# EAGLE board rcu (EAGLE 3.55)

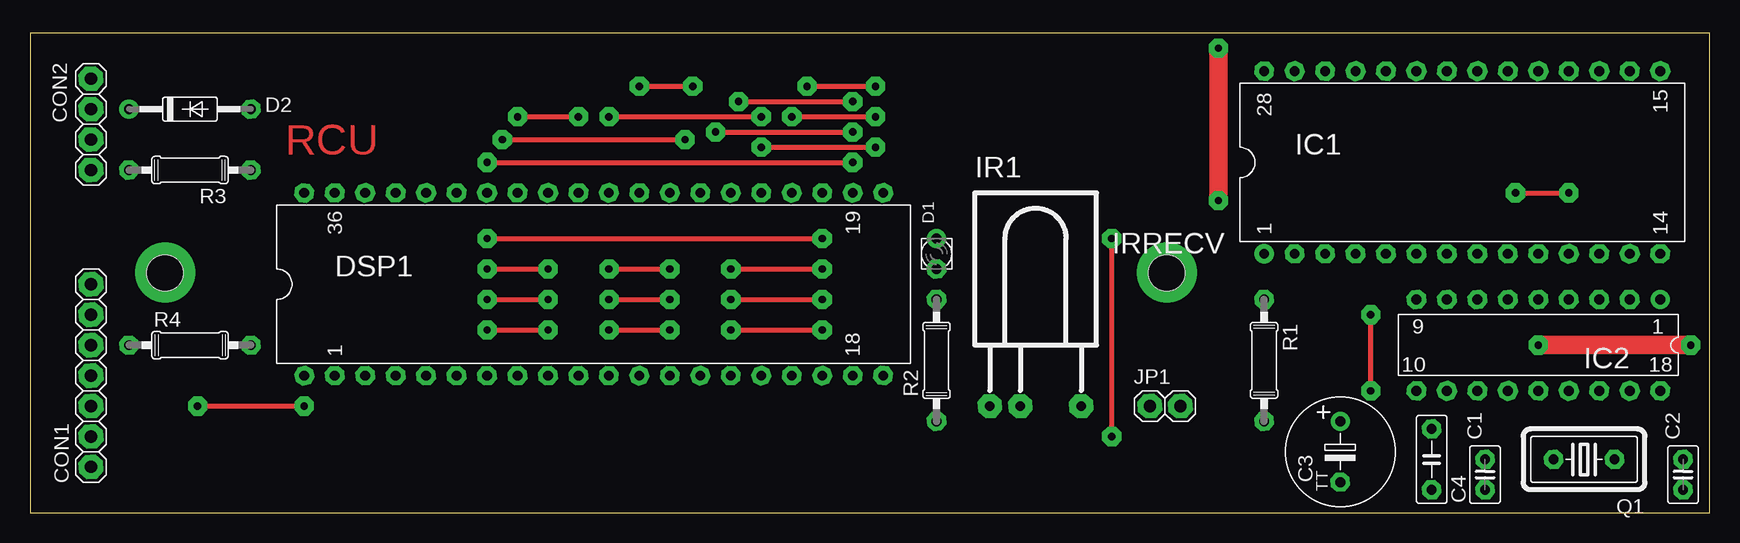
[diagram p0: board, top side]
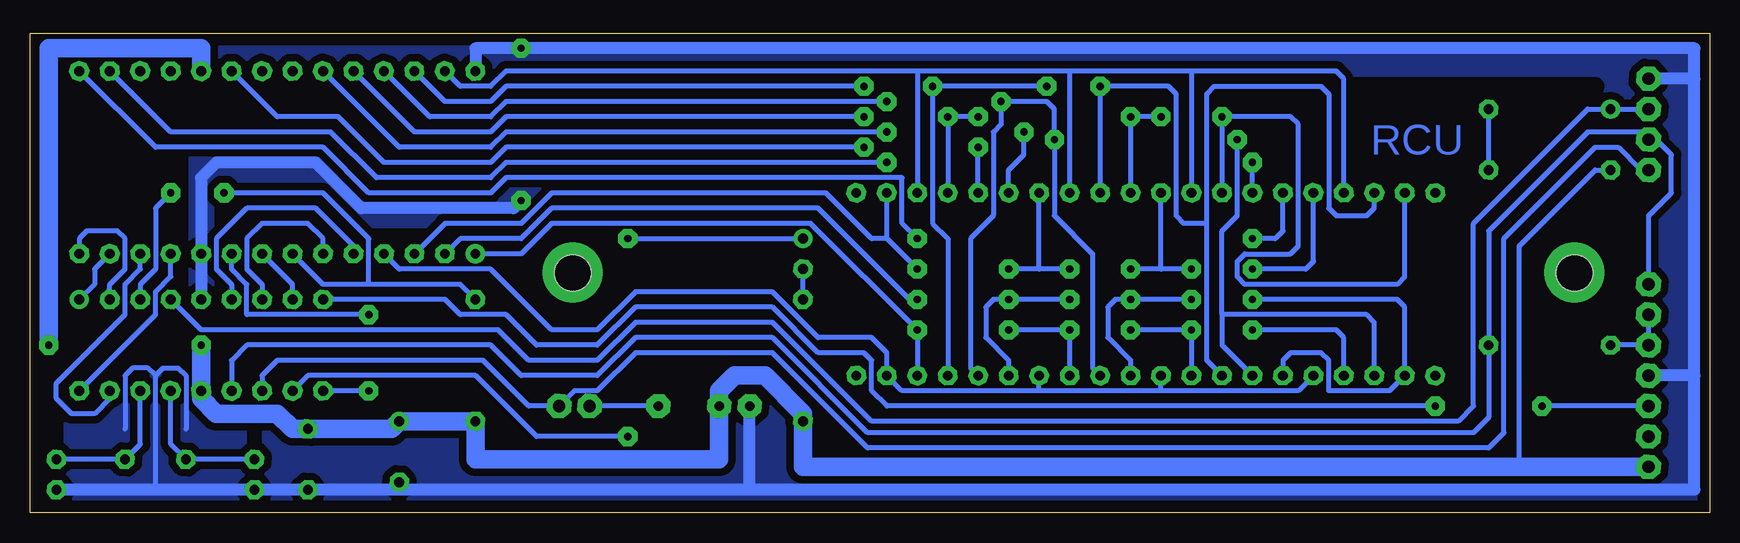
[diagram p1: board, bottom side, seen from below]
Size 140 x 40 mm. Coordinates in mm from the lower left corner, seen from the top.
Outline: 0,0 140,0 140,40 0,40 0,0
Copper layers used: Top, Bottom
bRestrict: 12 lines

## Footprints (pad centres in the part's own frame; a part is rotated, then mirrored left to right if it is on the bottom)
,5-2 = drill 0.813 pad 1.6 octagon:  -1.27,0;  1.27,0
5D9 = drill 0.813 pad 1.6 octagon:  -2.54,0 | drill 0.813 pad 1.6 round:  2.54,0
B2,5 = drill 0.813 pad 1.6 octagon:  -2.54,0;  2.54,0
07 = drill 1.016 pad 2.032 octagon:  -7.62,0;  -5.08,0;  -2.54,0;  0,0;  2.54,0;  5.08,0;  7.62,0
04 = drill 1.016 pad 2.032 octagon:  -3.81,0;  -1.27,0;  1.27,0;  3.81,0
D2 = drill 0.813 pad 1.6 octagon:  -1.27,0 | drill 0.813 pad 1.6 round:  1.27,0
35-10 = drill 0.813 pad 1.6 round:  -5.08,0 | drill 0.813 pad 1.6 octagon:  5.08,0
L36+4 = drill 0.813 pad 1.6 octagon:  -21.59,-7.62;  -19.05,-7.62;  -16.51,-7.62;  -13.97,-7.62;  -11.43,-7.62;  -8.89,-7.62;  -6.35,-7.62;  -3.81,-7.62;  -1.27,-7.62;  1.27,-7.62;  3.81,-7.62;  6.35,-7.62;  8.89,-7.62;  11.43,-7.62;  13.97,-7.62;  16.51,-7.62;  19.05,-7.62;  21.59,-7.62;  21.59,7.62;  19.05,7.62;  16.51,7.62;  13.97,7.62;  11.43,7.62;  8.89,7.62;  6.35,7.62;  3.81,7.62;  1.27,7.62;  -1.27,7.62;  -3.81,7.62;  -6.35,7.62;  -8.89,7.62;  -11.43,7.62;  -13.97,7.62;  -16.51,7.62;  -19.05,7.62;  -21.59,7.62;  -24.13,7.62;  -24.13,-7.62;  24.13,-7.62;  24.13,7.62
L28-6 = drill 0.813 pad 1.6 round:  -16.51,-7.62 | drill 0.813 pad 1.6 octagon:  -13.97,-7.62;  -11.43,-7.62;  -8.89,-7.62;  -6.35,-7.62;  -3.81,-7.62;  -1.27,-7.62;  1.27,-7.62;  3.81,-7.62;  6.35,-7.62;  8.89,-7.62;  11.43,-7.62;  13.97,-7.62;  16.51,-7.62;  16.51,7.62;  13.97,7.62;  11.43,7.62;  8.89,7.62;  6.35,7.62;  3.81,7.62;  1.27,7.62;  -1.27,7.62;  -3.81,7.62;  -6.35,7.62;  -8.89,7.62;  -11.43,7.62;  -13.97,7.62;  -16.51,7.62
L18 = drill 0.813 pad 1.6 round:  -10.16,-3.81 | drill 0.813 pad 1.6 octagon:  -7.62,-3.81;  -5.08,-3.81;  -2.54,-3.81;  0,-3.81;  2.54,-3.81;  5.08,-3.81;  7.62,-3.81;  10.16,-3.81;  10.16,3.81;  7.62,3.81;  5.08,3.81;  2.54,3.81;  0,3.81;  -2.54,3.81;  -5.08,3.81;  -7.62,3.81;  -10.16,3.81
RECV = drill 0.813 pad 2 octagon:  -3.81,-12.7;  -1.27,-12.7;  3.81,-12.7
02 = drill 1.016 pad 2.032 octagon:  -1.27,0;  1.27,0
18U-V = drill 0.813 pad 1.6 octagon:  -2.54,0;  2.54,0
07/10 = drill 0.813 pad 1.6 octagon:  -5.08,0;  5.08,0
AME = hole 3: -41.75,0; 41.75,0

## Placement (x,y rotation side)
C1  27p  [,5-2]  121.28,3.17 90 top
C2  27p  [,5-2]  137.79,3.17 90 top
C3  10u/10V  [5D9]  109.22,5.08 90 top
C4  100n  [B2,5]  116.84,4.45 270 top
CON1  1x7  [07]  5.08,11.43 90 top
CON2  1x4  [04]  5.08,32.38 270 top
D1  LED2  [D2]  75.56,21.59 90 top
D2  1N4148  [35-10]  13.34,33.66 0 top
DSP1  LEDDISP  [L36+4]  46.99,19.05 0 top
IC1  ICM7218C  [L28-6]  119.38,29.21 0 top
IC2  16C84P  [L18]  125.73,13.97 180 top
IR1  IRRECV  [RECV]  83.82,21.59 0 top
JP1  1x2  [02]  94.61,8.89 0 top
Q1  10MHz  [18U-V]  129.54,4.45 180 top
R1  4k7  [07/10]  102.87,12.7 270 top
R2  470R  [07/10]  75.56,12.7 90 top
R3  2k2  [07/10]  13.34,28.57 180 top
R4  22k  [07/10]  13.34,13.97 0 top
U$2  [AME]  53,20 0 top

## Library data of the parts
C1 C2 C4 = cap-wi
C3 = cap-tant
CON1 CON2 JP1 = pinhead
D1 = led
D2 = diode
DSP1 IR1 U$2 = display
IC1 = maxim
IC2 = pic
Q1 = quartz
R1-R4 = r

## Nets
+5V: C3. C4. CON1. IC1. IC2. IR1. R1. R2. R3.
DIGIT1: DSP1. IC1.
DIGIT2: DSP1. IC1.
DIGIT3: DSP1. IC1.
DIGIT4: DSP1. IC1.
DP: DSP1. IC1.
GND: C1. C2. C3. C4. CON1. CON2. IC1. IC2. IR1.
N$1: IC1. IC2.
N$2: IC1. IC2.
N$3: C1. IC2. Q1.
N$4: IC1. IC2.
N$5: IC1. IC2.
N$6: IC1. IC2.
N$7: IC1. IC2.
N$8: IC1. IC2. R1.
N$9: IC1. IC2.
N$10: IC1. IC2.
N$11: C2. IC2. Q1.
N$12: D1. R2.
N$13: D1. IC2.
N$14: CON2. D2. IC2.
N$15: CON1. CON2. IC2. R4.
N$16: CON2. IC2. JP1.
N$17: D2. R3.
N$18: CON1. R4.
N$19: IR1. JP1.
N$20: CON1. IC2.
SEG0: DSP1. IC1.
SEG1: DSP1. IC1.
SEG2: DSP1. IC1.
SEG3: DSP1. IC1.
SEG4: DSP1. IC1.
SEG5: DSP1. IC1.
SEG6: DSP1. IC1.

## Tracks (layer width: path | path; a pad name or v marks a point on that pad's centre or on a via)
+5V  (via drill 0.61 pad 1.6)
  Top 1.524: v125.73,13.97 v138.43,13.97
  Bottom 0.406: 15.88,3.81 15.88,22.23 9.53,28.57 R3.
  Bottom 1.016: 75.56,7.62 75.56,8.26
  Bottom 1.524: v125.73,13.97 125.73,10.16 125.73,9.53 124.46,8.26 119.38,8.26 118.11,6.99 116.84,6.99 109.86,6.99 C3. R1. 102.87,4.45 82.55,4.45 82.55,8.89 82.55,10.16 81.28,11.43 78.74,11.43 75.56,8.26 | v138.43,13.97 138.43,38.73 125.73,38.73 125.73,36.83 | 75.56,7.62 75.56,3.81 15.88,3.81 5.08,3.81
DIGIT1  (via drill 0.61 pad 1.6)
  Top 0.406: v38.1,22.86 v66.04,22.86
  Bottom 0.406: 135.89,36.83 129.54,30.48 115.57,30.48 111.76,26.67 101.6,26.67 100.33,27.94 67.31,27.94 67.31,24.13 v66.04,22.86 | v38.1,22.86 36.2,22.86 35.56,23.5 35.56,26.67
DIGIT2  (via drill 0.61 pad 1.6)
  Top 0.406: v38.1,29.21 v68.58,29.21
  Bottom 0.406: 133.35,36.83 128.27,31.75 114.94,31.75 111.12,27.94 101.6,27.94 100.33,29.21 v68.58,29.21 | 38.1,26.67 v38.1,29.21
DIGIT3  (via drill 0.61 pad 1.6)
  Top 0.406: v57.15,31.75 v68.58,31.75
  Bottom 0.406: 115.57,36.83 109.22,30.48 101.6,30.48 100.33,31.75 v68.58,31.75 | 58.42,26.67 58.42,28.57 57.15,29.84 v57.15,31.75
DIGIT4  (via drill 0.61 pad 1.6)
  Top 0.406: v60.96,30.48 v70.48,30.48
  Bottom 0.406: 123.19,36.83 119.38,33.02 114.3,33.02 110.49,29.21 101.6,29.21 100.33,30.48 v70.48,30.48 | 60.96,26.67 v60.96,30.48
DP
  Bottom 0.406: 110.49,21.59 109.22,20.32 101.6,20.32 96.52,15.24 92.71,15.24 89.53,18.41 78.11,18.41 74.3,14.61 69.85,14.61 68.58,13.34 68.58,11.43 67.31,10.16 55.88,10.16 | 33.02,11.43 34.29,10.16 45.72,10.16 | 45.72,10.16 45.72,11.43 | 45.72,10.16 55.88,10.16 | 55.88,10.16 55.88,11.43
GND  (via drill 0.61 pad 1.6)
  Top 1.524: v99.06,38.73 v99.06,26.04
  Bottom 0.406: 129.54,1.91 129.54,11.43 | 129.54,11.43 130.18,12.06 131.44,12.06 132.08,11.43 132.08,6.99 | 129.54,11.43 128.91,12.06 127.64,12.06 127,11.43 127,6.99
  Bottom 1.016: 137.79,1.91 129.54,1.91 121.28,1.91 C4. 109.22,1.91 | 109.22,1.91 109.22,2.54 | 125.73,17.78 125.73,21.59 125.73,27.94 124.46,29.21 116.2,29.21 112.39,25.4 99.69,25.4 v99.06,26.04 | 80.01,1.91 80.01,8.89 | 1.27,11.43 1.27,36.2 | 80.01,1.91 1.27,1.91 1.27,11.43 | 80.01,1.91 109.22,1.91 | IC1. 102.87,38.73 v99.06,38.73 1.27,38.73 1.27,36.2 | 1.27,11.43 5.08,11.43 | 1.27,36.2 5.08,36.2
  pour Bottom (isolate 0.635, no thermals): 0.13,39.88 0.13,0.13 139.83,0.13 139.83,39.88
N$1
  Bottom 0.406: 123.19,17.78 123.19,19.05 124.46,20.32 124.46,22.86 121.92,25.4 116.2,25.4 113.03,22.23 113.03,21.59
N$2
  Bottom 0.406: 120.65,17.78 120.65,19.05 121.92,20.32 121.92,22.86 120.65,24.13 116.84,24.13 115.57,22.86 115.57,21.59
N$3
  Bottom 0.406: 128.27,10.16 128.27,5.71 Q1. C1.
N$4
  Bottom 0.406: 130.81,21.59 130.81,20.32 132.08,19.05 132.08,16.51 137.79,10.79 137.79,9.53 136.53,8.26 134.62,8.26 133.35,9.53 133.35,10.16
N$5
  Bottom 0.406: 128.27,21.59 128.27,19.68 129.54,18.41 129.54,16.51 IC2.
N$6
  Bottom 0.406: 133.35,21.59 134.62,20.32 134.62,19.05 135.89,17.78
N$7
  Bottom 0.406: 135.89,21.59 135.89,22.86 135.25,23.5 132.72,23.5 132.08,22.86 132.08,20.32 133.35,19.05 133.35,17.78
N$8  (via drill 0.61 pad 1.6)
  Top 0.406: v123.83,26.67 v128.27,26.67
  Bottom 0.406: 118.11,21.59 115.57,19.05 111.76,19.05 | 111.76,19.05 104.14,19.05 102.87,17.78 | 130.81,17.78 130.81,19.05 129.54,20.32 129.54,25.4 v128.27,26.67 | 111.76,19.05 111.76,22.86 115.57,26.67 v123.83,26.67
N$9  (via drill 0.61 pad 1.6)
  Top 0.406: v111.76,10.16 v111.76,16.51
  Bottom 0.406: v111.76,10.16 115.57,10.16 | 123.19,21.59 123.19,20.32 121.92,19.05 121.92,16.51 v111.76,16.51
N$10
  Bottom 0.406: 120.65,21.59 118.11,19.05 118.11,17.78
N$11
  Bottom 0.406: 130.81,10.16 130.81,5.71 132.08,4.45 C2.
N$12
  Bottom 0.406: R2. 75.56,20.32
N$13  (via drill 0.61 pad 1.6)
  Top 0.406: v90.17,6.35 v90.17,22.86
  Bottom 0.406: 118.11,10.16 116.84,11.43 102.87,11.43 97.79,6.35 v90.17,6.35 | v90.17,22.86 D1.
N$14
  Bottom 0.406: 128.27,17.78 125.73,15.24 100.97,15.24 98.42,12.7 92.71,12.7 89.53,15.88 78.11,15.88 69.85,7.62 20.95,7.62 19.68,8.89 19.68,24.13 10.16,33.66 8.26,33.66 5.08,33.66
N$15
  Bottom 0.406: 123.19,10.16 123.19,12.7 121.92,13.97 101.6,13.97 99.06,11.43 92.71,11.43 89.53,14.61 78.11,14.61 70.17,6.67 19.68,6.67 18.41,7.94 R4. 18.41,23.5 10.16,31.75 5.71,31.75 5.08,31.11 4.45,31.11 3.17,29.84 3.17,26.67 5.08,24.77 CON1.
N$16
  Bottom 0.406: 120.65,10.16 120.65,11.43 119.38,12.7 102.23,12.7 98.42,8.89 JP1. 94.61,10.16 92.71,10.16 89.53,13.34 78.11,13.34 70.17,5.4 18.41,5.4 17.14,6.67 17.14,22.86 9.53,30.48 7.62,30.48 5.71,28.57 CON2.
N$17
  Bottom 0.406: 18.41,28.57 D2.
N$18
  Bottom 0.406: 5.08,16.51 5.08,13.97 8.26,13.97
N$19
  Bottom 0.406: IR1. 93.34,8.89
N$20  (via drill 0.61 pad 1.6)
  Top 0.406: v13.97,8.89 v22.86,8.89
  Bottom 0.406: 115.57,17.78 105.41,17.78 104.14,16.51 100.33,16.51 97.79,13.97 92.71,13.97 89.53,17.14 78.11,17.14 74.3,13.34 70.48,13.34 69.85,12.7 69.85,10.16 68.58,8.89 v22.86,8.89 | 5.08,8.89 v13.97,8.89
N$21  (via drill 0.61 pad 5)
  other vias: 11.25,20.01
N$22  (via drill 0.61 pad 5)
  other vias: 94.76,20.01
SEG0
  Bottom 0.406: 105.41,36.83 104.14,35.56 101.6,35.56 100.33,36.83 66.04,36.83 | 30.48,26.67 30.48,36.2 31.11,36.83 43.18,36.83 | 43.18,36.83 43.18,26.67 | 53.34,36.83 53.34,26.67 | 66.04,36.83 66.04,26.67 | 53.34,36.83 66.04,36.83 | 43.18,36.83 53.34,36.83
SEG1  (via drill 0.61 pad 1.6)
  Top 0.406: v58.42,20.32 v66.04,20.32 | v48.26,20.32 v53.34,20.32 | v38.1,20.32 v43.18,20.32
  Bottom 0.406: 107.95,21.59 105.41,24.13 99.06,24.13 96.52,26.67 73.66,26.67 69.85,22.86 68.58,22.86 | v38.1,20.32 33.66,20.32 33.02,20.95 33.02,26.67 | v43.18,20.32 45.72,20.32 | 45.72,20.32 v48.26,20.32 | v53.34,20.32 55.88,20.32 | 55.88,20.32 v58.42,20.32 | v66.04,20.32 68.58,22.86 | 68.58,22.86 68.58,26.67 | 45.72,20.32 45.72,26.67 | 55.88,20.32 55.88,26.67
SEG2  (via drill 0.61 pad 1.6)
  Top 0.406: v38.1,15.24 v43.18,15.24 | v48.26,15.24 v53.34,15.24 | v58.42,15.24 v66.04,15.24
  Bottom 0.406: 102.87,21.59 99.06,21.59 96.52,24.13 74.93,24.13 v66.04,15.24 66.04,11.43 | 30.48,11.43 30.48,14.61 31.11,15.24 v38.1,15.24 | 43.18,11.43 v43.18,15.24 v48.26,15.24 | 53.34,11.43 v53.34,15.24 v58.42,15.24
SEG3  (via drill 0.61 pad 1.6)
  Top 0.406: v59.05,34.29 v68.58,34.29 | v39.37,31.11 v54.61,31.11
  Bottom 0.406: 110.49,36.83 106.68,33.02 101.6,33.02 100.33,34.29 v68.58,34.29 | 60.96,11.43 61.59,12.06 61.59,22.86 59.69,24.77 59.69,31.75 59.05,32.38 v59.05,34.29 55.24,34.29 54.61,33.66 v54.61,31.11 54.61,24.77 51.44,21.59 51.44,12.06 50.8,11.43 | v39.37,31.11 39.37,24.77 40.64,23.5 40.64,16.51 | 40.64,16.51 40.64,13.97 38.1,11.43 | 27.94,11.43 27.94,15.88 28.57,16.51 40.64,16.51
SEG4  (via drill 0.61 pad 1.6)
  Top 0.406: v58.42,17.78 v66.04,17.78 | v48.26,17.78 v53.34,17.78 | v38.1,17.78 v43.18,17.78
  Bottom 0.406: 105.41,21.59 104.14,22.86 99.06,22.86 96.52,25.4 74.3,25.4 66.67,17.78 v66.04,17.78 | 58.42,11.43 58.42,12.7 60.33,14.61 60.33,17.14 59.69,17.78 v58.42,17.78 v53.34,17.78 | 48.26,11.43 48.26,12.7 50.16,14.61 50.16,17.14 49.53,17.78 v48.26,17.78 v43.18,17.78 | 35.56,11.43 35.56,12.7 34.92,13.34 32.38,13.34 31.75,12.7 31.75,10.16 26.67,10.16 25.4,11.43 25.4,17.14 26.04,17.78 v38.1,17.78
SEG5  (via drill 0.61 pad 1.6)
  Top 0.406: v40.64,33.02 v45.72,33.02 | v48.26,33.02 v60.96,33.02 | v63.5,33.02 v70.48,33.02
  Bottom 0.406: 113.03,36.83 107.95,31.75 101.6,31.75 100.33,33.02 v70.48,33.02 | 63.5,26.67 v63.5,33.02 v60.96,33.02 | 48.26,26.67 v48.26,33.02 v45.72,33.02 | 40.64,26.67 v40.64,33.02 34.92,33.02 34.29,32.38 34.29,22.23 34.92,21.59 38.73,21.59 39.37,20.95 39.37,19.68 38.73,19.05 26.04,19.05 25.4,19.68 25.4,26.67
SEG6  (via drill 0.61 pad 1.6)
  Top 0.406: v64.77,35.56 v70.48,35.56 | v50.8,35.56 v55.24,35.56
  Bottom 0.406: 107.95,36.83 105.41,34.29 101.6,34.29 100.33,35.56 v70.48,35.56 | 63.5,11.43 63.5,22.86 64.77,24.13 v64.77,35.56 v55.24,35.56 | 40.64,11.43 41.91,12.7 41.91,24.13 | 41.91,24.13 41.91,34.92 41.27,35.56 32.38,35.56 31.75,34.92 31.75,25.4 31.11,24.77 28.57,24.77 27.94,25.4 27.94,26.67 | 50.8,26.67 v50.8,35.56 45.09,35.56 44.45,34.92 44.45,24.77 43.81,24.13 41.91,24.13

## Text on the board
Top: RCU
Bottom: RCU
